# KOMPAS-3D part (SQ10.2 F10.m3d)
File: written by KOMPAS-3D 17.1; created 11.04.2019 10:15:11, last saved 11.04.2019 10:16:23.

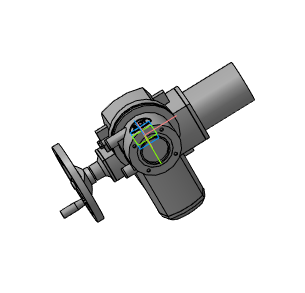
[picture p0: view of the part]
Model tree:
1. Операция без истории:2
